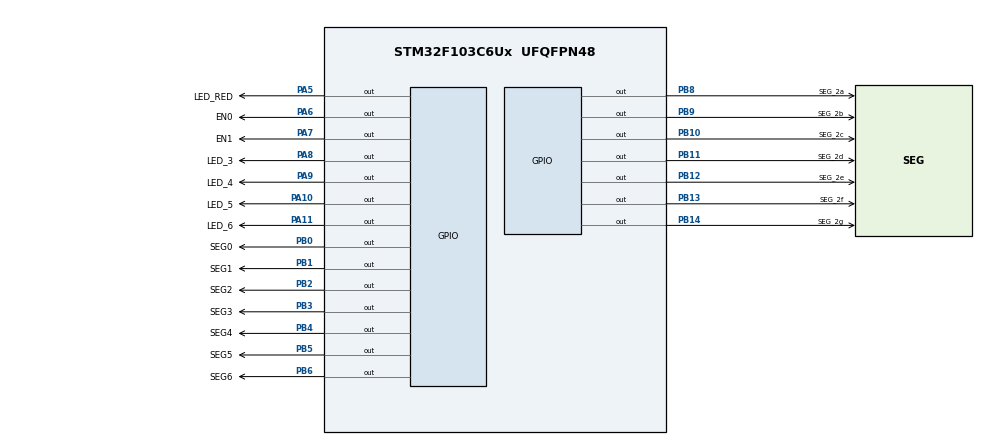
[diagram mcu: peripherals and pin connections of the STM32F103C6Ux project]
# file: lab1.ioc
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Mcu.Family=STM32F1
Mcu.Name=STM32F103C6Ux
Mcu.Package=UFQFPN48
<<<<<<< HEAD
=======
>>>>>>> Ex1
NVIC.PriorityGroup=NVIC_PRIORITYGROUP_4
NVIC.TIM2_IRQn=true\:0\:0\:false\:false\:true\:true\:true\:true
<<<<<<< HEAD
PA10.GPIO_Label=LED_5
PA10.Signal=GPIO_Output
PA11.GPIO_Label=LED_6
PA11.Signal=GPIO_Output
=======
>>>>>>> Ex1
PA13.Mode=Serial_Wire
PA13.Signal=SYS_JTMS-SWDIO
PA14.Mode=Serial_Wire
PA14.Signal=SYS_JTCK-SWCLK
<<<<<<< HEAD
PA5.GPIO_Label=LED_PA5
PA5.Signal=GPIO_Output
PA6.GPIO_Label=LED_1
PA6.Signal=GPIO_Output
PA7.GPIO_Label=LED_2
PA7.Signal=GPIO_Output
PA8.GPIO_Label=LED_3
PA8.Signal=GPIO_Output
PA9.GPIO_Label=LED_4
PA9.Signal=GPIO_Output
PB0.GPIO_Label=SEG_a
PB0.Signal=GPIO_Output
PB1.GPIO_Label=SEG_b
PB1.Signal=GPIO_Output
PB10.GPIO_Label=SEG_2c
PB10.Signal=GPIO_Output
PB11.GPIO_Label=SEG_2d
PB11.Signal=GPIO_Output
PB12.GPIO_Label=SEG_2e
PB12.Signal=GPIO_Output
PB13.GPIO_Label=SEG_2f
PB13.Signal=GPIO_Output
PB14.GPIO_Label=SEG_2g
PB14.Signal=GPIO_Output
PB2.GPIO_Label=SEG_c
PB2.Signal=GPIO_Output
PB3.GPIO_Label=SEG_d
PB3.Signal=GPIO_Output
PB4.GPIO_Label=SEG_e
PB4.Signal=GPIO_Output
PB5.GPIO_Label=SEG_f
PB5.Signal=GPIO_Output
PB6.GPIO_Label=SEG_g
PB6.Signal=GPIO_Output
PB8.GPIO_Label=SEG_2a
PB8.Signal=GPIO_Output
PB9.GPIO_Label=SEG_2b
PB9.Signal=GPIO_Output
=======
PA5.GPIO_Label=LED_RED
PA5.Signal=GPIO_Output
PA6.GPIO_Label=EN0
PA6.Signal=GPIO_Output
PA7.GPIO_Label=EN1
PA7.Signal=GPIO_Output
PB0.GPIO_Label=SEG0
PB0.Signal=GPIO_Output
PB1.GPIO_Label=SEG1
PB1.Signal=GPIO_Output
PB2.GPIO_Label=SEG2
PB2.Signal=GPIO_Output
PB3.GPIO_Label=SEG3
PB3.Signal=GPIO_Output
PB4.GPIO_Label=SEG4
PB4.Signal=GPIO_Output
PB5.GPIO_Label=SEG5
PB5.Signal=GPIO_Output
PB6.GPIO_Label=SEG6
PB6.Signal=GPIO_Output
>>>>>>> Ex1
ProjectManager.HeapSize=0x200
<<<<<<< HEAD
=======
>>>>>>> Ex1
ProjectManager.StackSize=0x400
ProjectManager.TargetToolchain=STM32CubeIDE
RCC.APB1Freq_Value=8000000
RCC.APB2Freq_Value=8000000
<<<<<<< HEAD
TIM2.Period=79
TIM2.Prescaler=999
=======
TIM2.Period=9
TIM2.Prescaler=7999
>>>>>>> Ex1
VP_TIM2_VS_ClockSourceINT.Mode=Internal
board=custom

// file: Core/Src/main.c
/* USER CODE BEGIN Header */
/**
  ******************************************************************************
  * @file           : main.c
  * @brief          : Main program body
  ******************************************************************************
  * @attention
  *
  * Copyright (c) 2025 STMicroelectronics.
  * All rights reserved.
  *
  * This software is licensed under terms that can be found in the LICENSE file
  * in the root directory of this software component.
  * If no LICENSE file comes with this software, it is provided AS-IS.
  *
  ******************************************************************************
  */
/* USER CODE END Header */
#include "main.h"

TIM_HandleTypeDef htim2;

void SystemClock_Config(void);
static void MX_GPIO_Init(void);
static void MX_TIM2_Init(void);

int main(void)
{

  /* MCU Configuration--------------------------------------------------------*/

  /* Reset of all peripherals, Initializes the Flash interface and the Systick. */
  HAL_Init();

  /* Configure the system clock */
  SystemClock_Config();

  /* Initialize all configured peripherals */
  MX_GPIO_Init();
  MX_TIM2_Init();
  /* USER CODE BEGIN 2 */
//  HAL_TIM_Base_Start_IT(&htim2);
  int state = 0;
  int counter = 0;
  /* USER CODE END 2 */

  /* Infinite loop */
  while (1)
  {

    /* USER CODE BEGIN 3 */
	  switch(state) {
	  case 0: // INIT
		  HAL_GPIO_WritePin(GPIOA, LED_RED_Pin, 1);
		  HAL_GPIO_WritePin(GPIOA, LED_YELLOW_Pin, 1);
<<<<<<<< HEAD:CO3010_STM32_Lab_1/Ex2/STM32/Core/Src/main.c
		  HAL_GPIO_WritePin(GPIOA, LED_GREEN_Pin, 1);
		  counter = 1;
========
		  counter = 2;
>>>>>>>> Ex1:CO3010_STM32_Lab_1/Ex1/STM32/Core/Src/main.c
		  state = 1;
		  break;
	  case 1: // RED
		  --counter;
		  if (counter <= 0) {
		 	HAL_GPIO_WritePin(GPIOA, LED_RED_Pin, 0);
		 	HAL_GPIO_WritePin(GPIOA, LED_YELLOW_Pin, 1);
<<<<<<<< HEAD:CO3010_STM32_Lab_1/Ex2/STM32/Core/Src/main.c
		 	HAL_GPIO_WritePin(GPIOA, LED_GREEN_Pin, 1);
		 	counter = 5;
		 	state = 3;
========
		 	counter = 2;
		 	state = 2;
>>>>>>>> Ex1:CO3010_STM32_Lab_1/Ex1/STM32/Core/Src/main.c
		  }
		  break;
	  case 2: // YELLOW
		  --counter;
		  if (counter <= 0) {
			 HAL_GPIO_WritePin(GPIOA, LED_RED_Pin, 1);
			 HAL_GPIO_WritePin(GPIOA, LED_YELLOW_Pin, 0);
<<<<<<<< HEAD:CO3010_STM32_Lab_1/Ex2/STM32/Core/Src/main.c
			 HAL_GPIO_WritePin(GPIOA, LED_GREEN_Pin, 1);
========
>>>>>>>> Ex1:CO3010_STM32_Lab_1/Ex1/STM32/Core/Src/main.c
			 counter = 2;
			 state = 1;
		  }
	  	  break;
	  case 3: // GREEN, next is RED for 5s
	  		--counter;
	  	 if (counter <= 0) {
	  		HAL_GPIO_WritePin(GPIOA, LED_RED_Pin, 1);
	  		HAL_GPIO_WritePin(GPIOA, LED_YELLOW_Pin, 1);
	  		HAL_GPIO_WritePin(GPIOA, LED_GREEN_Pin, 0);
	  		counter = 3;
	  		state = 2;
	  	 }
	  	 break;
	  default:
	  	  break;
	  }
	  HAL_Delay(1000);
  }
  /* USER CODE END 3 */
}

void SystemClock_Config(void)
{
  RCC_OscInitTypeDef RCC_OscInitStruct = {0};
  RCC_ClkInitTypeDef RCC_ClkInitStruct = {0};

  /** Initializes the RCC Oscillators according to the specified parameters
  * in the RCC_OscInitTypeDef structure.
  */
  RCC_OscInitStruct.OscillatorType = RCC_OSCILLATORTYPE_HSI;
  RCC_OscInitStruct.HSIState = RCC_HSI_ON;
  RCC_OscInitStruct.HSICalibrationValue = RCC_HSICALIBRATION_DEFAULT;
  RCC_OscInitStruct.PLL.PLLState = RCC_PLL_NONE;
  if (HAL_RCC_OscConfig(&RCC_OscInitStruct) != HAL_OK)
  {
    Error_Handler();
  }

  /** Initializes the CPU, AHB and APB buses clocks
  */
  RCC_ClkInitStruct.ClockType = RCC_CLOCKTYPE_HCLK|RCC_CLOCKTYPE_SYSCLK
                              |RCC_CLOCKTYPE_PCLK1|RCC_CLOCKTYPE_PCLK2;
  RCC_ClkInitStruct.SYSCLKSource = RCC_SYSCLKSOURCE_HSI;
  RCC_ClkInitStruct.AHBCLKDivider = RCC_SYSCLK_DIV1;
  RCC_ClkInitStruct.APB1CLKDivider = RCC_HCLK_DIV1;
  RCC_ClkInitStruct.APB2CLKDivider = RCC_HCLK_DIV1;

  if (HAL_RCC_ClockConfig(&RCC_ClkInitStruct, FLASH_LATENCY_0) != HAL_OK)
  {
    Error_Handler();
  }
}

static void MX_TIM2_Init(void)
{

  TIM_ClockConfigTypeDef sClockSourceConfig = {0};
  TIM_MasterConfigTypeDef sMasterConfig = {0};

  htim2.Instance = TIM2;
  htim2.Init.Prescaler = 999;
  htim2.Init.CounterMode = TIM_COUNTERMODE_UP;
  htim2.Init.Period = 79;
  htim2.Init.ClockDivision = TIM_CLOCKDIVISION_DIV1;
  htim2.Init.AutoReloadPreload = TIM_AUTORELOAD_PRELOAD_DISABLE;
  if (HAL_TIM_Base_Init(&htim2) != HAL_OK)
  {
    Error_Handler();
  }
  sClockSourceConfig.ClockSource = TIM_CLOCKSOURCE_INTERNAL;
  if (HAL_TIM_ConfigClockSource(&htim2, &sClockSourceConfig) != HAL_OK)
  {
    Error_Handler();
  }
  sMasterConfig.MasterOutputTrigger = TIM_TRGO_RESET;
  sMasterConfig.MasterSlaveMode = TIM_MASTERSLAVEMODE_DISABLE;
  if (HAL_TIMEx_MasterConfigSynchronization(&htim2, &sMasterConfig) != HAL_OK)
  {
    Error_Handler();
  }

}

static void MX_GPIO_Init(void)
{
  GPIO_InitTypeDef GPIO_InitStruct = {0};

  /* GPIO Ports Clock Enable */
  __HAL_RCC_GPIOA_CLK_ENABLE();

  /*Configure GPIO pin Output Level */
  HAL_GPIO_WritePin(GPIOA, LED_RED_Pin|LED_YELLOW_Pin|LED_GREEN_Pin, GPIO_PIN_RESET);

  /*Configure GPIO pins : LED_RED_Pin LED_YELLOW_Pin LED_GREEN_Pin */
  GPIO_InitStruct.Pin = LED_RED_Pin|LED_YELLOW_Pin|LED_GREEN_Pin;
  GPIO_InitStruct.Mode = GPIO_MODE_OUTPUT_PP;
  GPIO_InitStruct.Pull = GPIO_NOPULL;
  GPIO_InitStruct.Speed = GPIO_SPEED_FREQ_LOW;
  HAL_GPIO_Init(GPIOA, &GPIO_InitStruct);

  /* USER CODE BEGIN MX_GPIO_Init_2 */
//  HAL_GPIO_WritePin(LED_RED_GPIO_Port, LED_RED_Pin, GPIO_PIN_SET);
  /* USER CODE END MX_GPIO_Init_2 */
}

/* USER CODE BEGIN 4 */
//int counter = 200;
//void HAL_TIM_PeriodElapsedCallback(TIM_HandleTypeDef *htim){
//	if (counter > 0) {
//		counter--;
//		if (counter <= 0) {
//			counter = 200;
//			HAL_GPIO_TogglePin(LED_RED_GPIO_Port, LED_RED_Pin);
//			HAL_GPIO_TogglePin(LED_YELLOW_GPIO_Port, LED_YELLOW_Pin);
//		}
//	}
//}
/* USER CODE END 4 */

void Error_Handler(void)
{
  __disable_irq();
  while (1)
  {
  }
}
